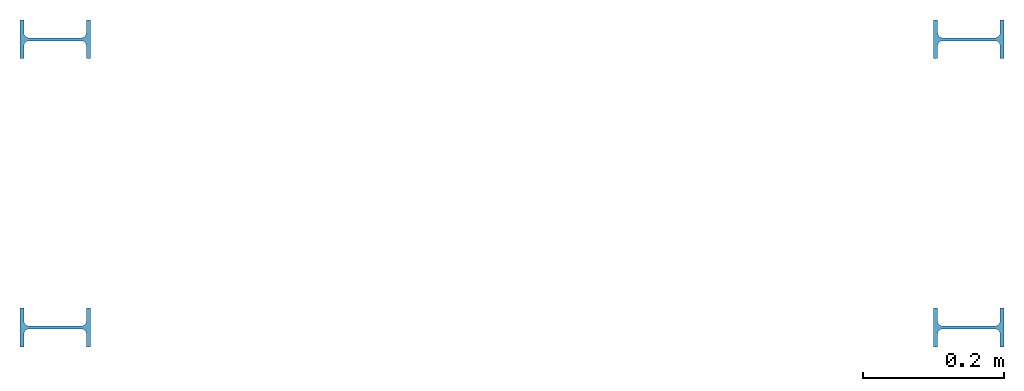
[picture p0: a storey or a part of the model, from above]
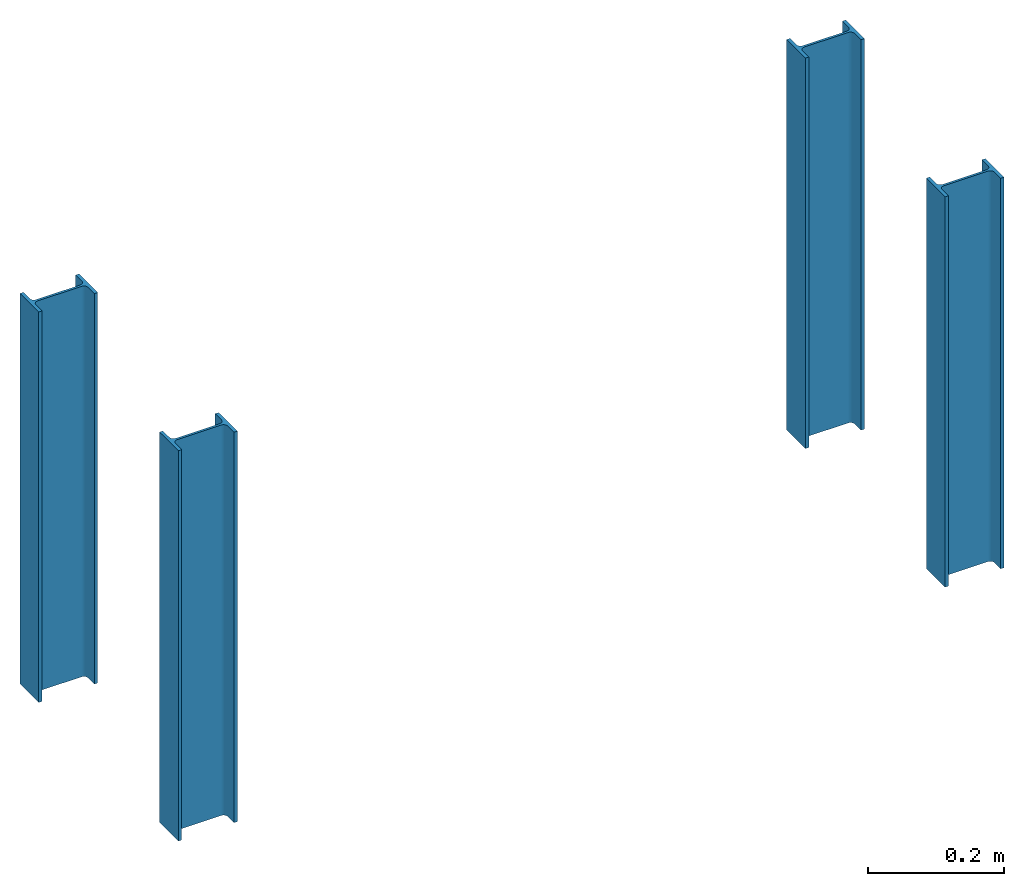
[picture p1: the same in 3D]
Properties of the parts of a building model (IFC4)

# File
Description: ViewDefinition [ReferenceView_V1.2], ExchangeRequirement [Architecture]
Time: 2024-05-21T20:58:24+01:00
Written by: ODA SDAI 22.12
Made in: 23.0.11.19 - Exporter 23.0.11.19 - Default UI

# IfcSite, Default
RefLatitude: 42, 24, 53, 508911; RefLongitude: -71, -15, -29, -58837; RefElevation: 0 mm
Pset_SiteCommon - Reference: Project Information

# IfcBuilding
Pset_BuildingCommon - Reference: Project Information; NumberOfStoreys: 4
Pset_BuildingElementProxyCommon - Reference: Project Information; IsExternal: no
Pset_BuildingStoreyCommon - Reference: Project Information; sets with these values: 2

# IfcBuildingStorey: Level:Level 1 (4)
Pset_BuildingStoreyCommon - Reference: Level 1
Name | LongName | Elevation (mm)
Base_Pilares | Base_Pilares | -950
Cabeza_Plares | Cabeza_Plares | -130
Base_Canal | Base_Canal | -0.03
Level 1 | Level 1 | 0

# IfcBeam: Equal L:L40x4 (4)
In: Level 1
Type - PredefinedType: BEAM; Material: Structural Steel - S235
Type - Pset_BeamCommon - IsExternal: no; LoadBearing: yes
Pset_BeamCommon - Slope: 0 deg; Reference: L40x4; Span: 1039.2 mm
Pset_EnvironmentalImpactIndicators - Reference: L40x4; sets with these values: 2
Qto_BeamBaseQuantities - Length: 1039.2 mm; CrossSectionArea: 0.000307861 m2; OuterSurfaceArea: 0.16092 m2; GrossSurfaceArea: 0.161535 m2; NetSurfaceArea: 0.161536 m2; GrossVolume: 0.00031993 m3; NetVolume: 0.000319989 m3
Name (Equal L:L40x4:...) | Roll (deg)
55671 | 270
56333 | 180
56356 | 90
65531 | 0

# IfcBeam: IPE:IPE220 (4)
In: Cabeza_Plares
Type - PredefinedType: BEAM; Material: Structural Steel - S235
Type - Pset_BeamCommon - IsExternal: no; LoadBearing: yes
Pset_BeamCommon - Reference: IPE220; Slope: 0 deg; Roll: 0 deg
Pset_EnvironmentalImpactIndicators - Reference: IPE220; sets with these values: 2
Qto_BeamBaseQuantities - CrossSectionArea: 0.00333715 m2
Name (IPE:IPE220:...) | Span (mm) = Length (mm) | OuterSurfaceArea (m2) | GrossSurfaceArea (m2) | NetSurfaceArea (m2) | GrossVolume (m3) | NetVolume (m3)
39670 | 1500 | 1.2714 | 1.27807 | 1.27808 | 0.00500573 | 0.00500824
39671 | 1500 | 1.2714 | 1.27807 | 1.27808 | 0.00500573 | 0.00500824
51243 | 300 | 0.254279 | 0.260954 | 0.260964 | 0.00100115 | 0.00100165
51244 | 300 | 0.254279 | 0.260954 | 0.260964 | 0.00100115 | 0.00100165

# IfcColumn: IPE Column:IPE100 (4)
In: Base_Pilares
Type - PredefinedType: COLUMN; Material: Structural Steel - S235
Type - Pset_ColumnCommon - IsExternal: no; LoadBearing: yes
Qto_ColumnBaseQuantities - Length: 700 mm; CrossSectionArea: 0.00103265 m2; OuterSurfaceArea: 0.279848 m2; GrossVolume: 0.000722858 m3; NetVolume: 0.000693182 m3
Pset_ColumnCommon - Slope: 0 deg; Reference: IPE100; Roll: 90 deg
Pset_EnvironmentalImpactIndicators - Reference: IPE100; sets with these values: 2
Name (IPE Column:IPE100:...)
51128
51129
51170
51172

# IfcSlab: Floor:MyFloorType-Variable, Floor:MyFloorType-Variable:69552
In: Base_Canal
Type - PredefinedType: FLOOR; Material: Glass 1
Type - Pset_SlabCommon - IsExternal: no
Pset_EnvironmentalImpactIndicators - Reference: MyFloorType-Variable; sets with these values: 2
Pset_SlabCommon - LoadBearing: yes; Reference: MyFloorType-Variable; PitchAngle: 0 deg
Qto_SlabBaseQuantities - Perimeter: 13.2546 mm; NetVolume: 0.0233116 m3

# IfcWall: Basic Wall:MyWall-Variable (4)
In: Base_Canal
Type - PredefinedType: STANDARD
Type - Pset_WallCommon - IsExternal: yes
Material: Glass
Qto_WallBaseQuantities - Width: 10 mm
Pset_EnvironmentalImpactIndicators - Reference: MyWall-Variable; sets with these values: 2
Pset_WallCommon - Reference: MyWall-Variable; LoadBearing: no; ExtendToStructure: no
Name (Basic Wall:MyWall-Variable:...) | Height (mm) | Length (mm) | GrossFootprintArea (m2) | GrossVolume (m3) = NetVolume (m3) | GrossSideArea (m2) = NetSideArea (m2)
2854 | 1000 | 1500 | 0.015 | 0.015 | 1.5
2964 | 1000 | 1500 | 0.015 | 0.015 | 1.5
69436 | 1030 | 520 | 0.0052 | 0.005356 | 0.5356
69437 | 1030 | 520 | 0.0052 | 0.005356 | 0.5356
